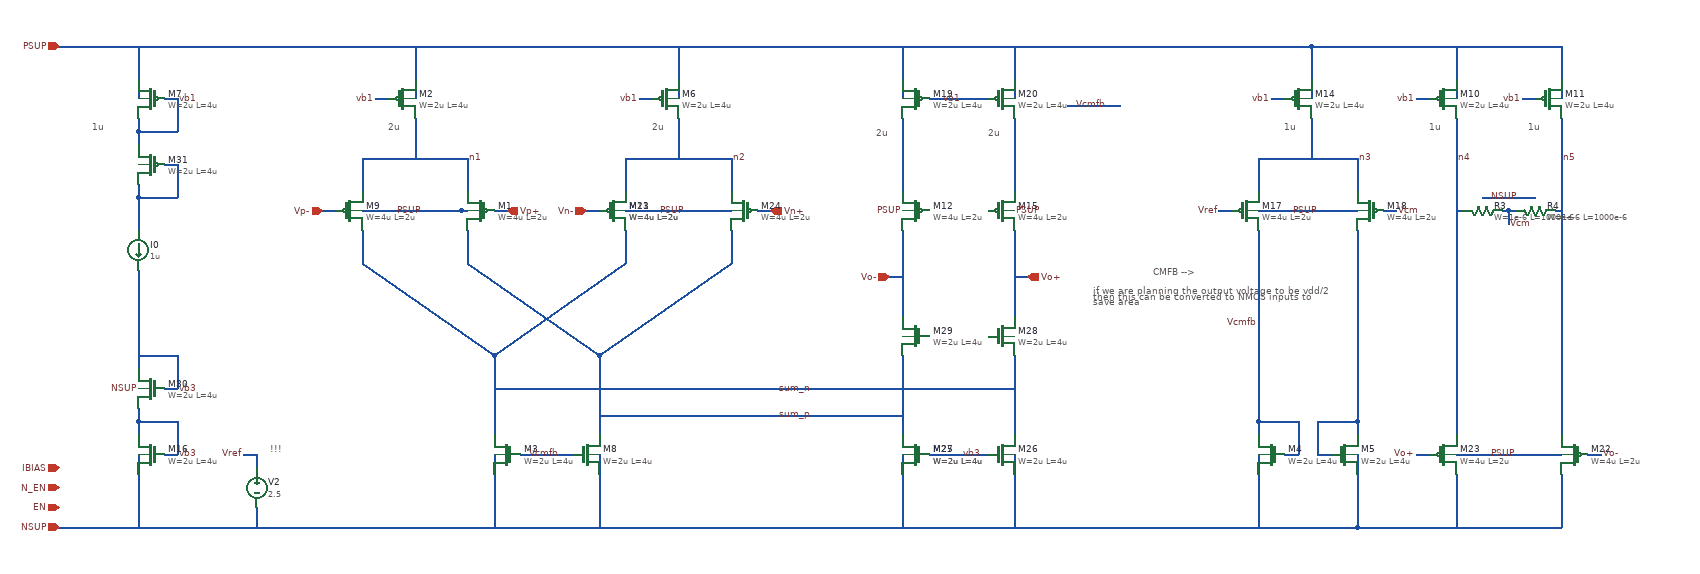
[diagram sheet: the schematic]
v {xschem version=3.4.7 file_version=1.2}
G {}
K {}
V {}
S {}
E {}
T {1u} -620 -620 0 0 0.4 0.4 {}
T {!!!} -350 -130 0 0 0.4 0.4 {}
T {1u} 1410 -620 0 0 0.4 0.4 {}
T {1u} 1560 -620 0 0 0.4 0.4 {}
T {2u} -170 -620 0 0 0.4 0.4 {}
T {2u} 230 -620 0 0 0.4 0.4 {}
T {1u} 1190 -620 0 0 0.4 0.4 {}
T {CMFB -->} 990 -400 0 0 0.4 0.4 {}
T {if we are planning the output voltage to be vdd/2
then this can be converted to NMOS inputs to 
save area} 900 -370 0 0 0.2 0.2 {}
T {2u} 570 -610 0 0 0.4 0.4 {}
T {2u} 740 -610 0 0 0.4 0.4 {}
N -660 -730 -260 -730 {lab=PSUP}
N -670 -730 -660 -730 {lab=PSUP}
N -550 -680 -550 -650 {lab=PSUP}
N -550 -730 -550 -680 {lab=PSUP}
N -550 -600 -490 -600 {lab=vb1}
N -490 -160 -490 -110 {lab=vb3}
N -550 -160 -490 -160 {lab=vb3}
N -550 -160 -550 -140 {lab=vb3}
N -510 -110 -490 -110 {lab=vb3}
N -670 0 -230 0 {lab=NSUP}
N -550 -80 -550 0 {lab=NSUP}
N -370 -30 -370 0 {lab=NSUP}
N -390 -110 -370 -110 {lab=Vref}
N -370 -110 -370 -90 {lab=Vref}
N -550 -110 -550 -80 {lab=NSUP}
N 1390 -110 1410 -110 {lab=Vo+}
N 1390 -110 1410 -110 {lab=Vo+}
N 1650 -110 1670 -110 {lab=Vo-}
N 1390 -650 1410 -650 {lab=vb1}
N 1390 -650 1410 -650 {lab=vb1}
N 1450 -620 1450 -140 {lab=n4}
N 1450 -80 1450 0 {lab=NSUP}
N 1450 -730 1450 -680 {lab=PSUP}
N 1610 -620 1610 -140 {lab=n5}
N 1610 -80 1610 0 {lab=NSUP}
N 1610 -730 1610 -680 {lab=PSUP}
N 1460 -110 1600 -110 {lab=PSUP}
N -210 -560 -210 -510 {lab=n1}
N -50 -560 -50 -510 {lab=n1}
N -10 -80 -10 0 {lab=NSUP}
N -230 0 -40 0 {lab=NSUP}
N -10 -110 -10 -80 {lab=NSUP}
N -10 -150 -10 -140 {lab=sum_n}
N -10 -160 -10 -150 {lab=sum_n}
N -130 -620 -130 -560 {lab=n1}
N -130 -730 -130 -680 {lab=PSUP}
N -210 -450 -210 -400 {lab=sum_n}
N -40 0 340 0 {lab=NSUP}
N 270 -680 270 -650 {lab=PSUP}
N -190 -650 -170 -650 {lab=vb1}
N 210 -650 230 -650 {lab=vb1}
N -10 -480 10 -480 {lab=Vp+}
N -270 -480 -250 -480 {lab=Vp-}
N 1150 -560 1150 -510 {lab=n3}
N 1300 -560 1300 -510 {lab=n3}
N 1230 -620 1230 -560 {lab=n3}
N 1150 -450 1150 -350 {lab=Vcmfb}
N 1300 -450 1300 -400 {lab=#net1}
N 1170 -650 1190 -650 {lab=vb1}
N 1090 -480 1110 -480 {lab=Vref}
N 1150 -80 1150 0 {lab=NSUP}
N 1150 -110 1150 -80 {lab=NSUP}
N 1150 -160 1150 -140 {lab=Vcmfb}
N 1150 -350 1150 -160 {lab=Vcmfb}
N 150 -160 150 -140 {lab=sum_p}
N 1300 -80 1300 0 {lab=NSUP}
N 1300 -350 1300 -160 {lab=#net1}
N 1300 -400 1300 -350 {lab=#net1}
N 1340 -480 1360 -480 {lab=Vcm}
N 150 -110 150 -10 {lab=NSUP}
N 150 -10 150 0 {lab=NSUP}
N 270 -730 270 -680 {lab=PSUP}
N 1230 -620 1230 -560 {lab=n3}
N 1230 -680 1230 -650 {lab=PSUP}
N 1170 -650 1190 -650 {lab=vb1}
N 1230 -730 1230 -680 {lab=PSUP}
N -130 -680 -130 -650 {lab=PSUP}
N -10 -260 -10 -160 {lab=sum_n}
N -210 -480 -60 -480 {lab=PSUP}
N -210 -560 -60 -560 {lab=n1}
N 190 -560 190 -510 {lab=n2}
N 350 -560 350 -510 {lab=n2}
N 190 -560 350 -560 {lab=n2}
N 270 -620 270 -560 {lab=n2}
N -50 -450 -50 -400 {lab=sum_p}
N 350 -450 350 -400 {lab=sum_p}
N 1150 -480 1300 -480 {lab=PSUP}
N 1150 -560 1300 -560 {lab=n3}
N 330 -730 1230 -730 {lab=PSUP}
N 730 0 1300 0 {lab=NSUP}
N 1300 -110 1300 -80 {lab=NSUP}
N 1190 -110 1210 -110 {lab=Vcmfb}
N 1210 -160 1210 -110 {lab=Vcmfb}
N 1150 -160 1210 -160 {lab=Vcmfb}
N 1240 -110 1260 -110 {lab=#net1}
N 1240 -120 1240 -110 {lab=#net1}
N 1240 -160 1240 -120 {lab=#net1}
N 1240 -160 1300 -160 {lab=#net1}
N 1300 -160 1300 -140 {lab=#net1}
N 40 -110 110 -110 {lab=Vcmfb}
N 130 -480 150 -480 {lab=Vn-}
N 390 -480 410 -480 {lab=Vn+}
N 30 -110 40 -110 {lab=Vcmfb}
N -260 -730 -60 -730 {lab=PSUP}
N -60 -560 -50 -560 {lab=n1}
N -60 -480 -50 -480 {lab=PSUP}
N -210 -400 -10 -260 {lab=sum_n}
N -10 -260 190 -400 {lab=sum_n}
N -210 -480 -60 -480 {lab=PSUP}
N 190 -480 340 -480 {lab=PSUP}
N 190 -450 190 -400 {lab=sum_n}
N -50 -400 150 -260 {lab=sum_p}
N 150 -260 350 -400 {lab=sum_p}
N 150 -260 150 -160 {lab=sum_p}
N 340 -480 350 -480 {lab=PSUP}
N -510 -650 -490 -650 {lab=vb1}
N 1530 -480 1540 -480 {lab=Vcm}
N 1520 -480 1530 -480 {lab=Vcm}
N 1530 -480 1530 -460 {lab=Vcm}
N 1490 -500 1530 -500 {lab=NSUP}
N 1530 -500 1570 -500 {lab=NSUP}
N 1450 -110 1460 -110 {lab=PSUP}
N 1600 -110 1610 -110 {lab=PSUP}
N 1450 -480 1460 -480 {lab=n4}
N 1600 -480 1610 -480 {lab=n5}
N 1300 0 1610 0 {lab=NSUP}
N 1230 -730 1610 -730 {lab=PSUP}
N 1450 -680 1450 -650 {lab=PSUP}
N 1610 -680 1610 -650 {lab=PSUP}
N 1550 -650 1570 -650 {lab=vb1}
N 1550 -650 1570 -650 {lab=vb1}
N -60 -730 330 -730 {lab=PSUP}
N 340 0 730 0 {lab=NSUP}
N 870 -640 940 -640 {lab=Vcmfb}
N 860 -640 870 -640 {lab=Vcmfb}
N 610 -110 610 0 {lab=NSUP}
N 780 -110 780 0 {lab=NSUP}
N 650 -110 740 -110 {lab=vb3}
N 610 -450 610 -320 {lab=Vo-}
N 610 -620 610 -510 {lab=#net2}
N 610 -730 610 -650 {lab=PSUP}
N 650 -650 740 -650 {lab=vb1}
N 780 -730 780 -650 {lab=PSUP}
N 780 -620 780 -510 {lab=#net3}
N 780 -380 800 -380 {lab=Vo+}
N 780 -450 780 -320 {lab=Vo+}
N 590 -380 610 -380 {lab=Vo-}
N 610 -260 610 -140 {lab=sum_p}
N 780 -260 780 -140 {lab=sum_n}
N 150 -170 610 -170 {lab=sum_p}
N -10 -210 780 -210 {lab=sum_n}
N -490 -260 -490 -210 {lab=vb3}
N -550 -260 -490 -260 {lab=vb3}
N -550 -260 -550 -240 {lab=vb3}
N -510 -210 -490 -210 {lab=vb3}
N -550 -180 -550 -160 {lab=vb3}
N -550 -390 -550 -240 {lab=vb3}
N -490 -650 -490 -600 {lab=vb1}
N -550 -620 -550 -600 {lab=vb1}
N -550 -500 -490 -500 {lab=#net4}
N -490 -550 -490 -500 {lab=#net4}
N -550 -520 -550 -500 {lab=#net4}
N -510 -550 -490 -550 {lab=#net4}
N -550 -600 -550 -580 {lab=vb1}
N -550 -500 -550 -450 {lab=#net4}
C {noconn.sym} -670 -60 0 1 {name=l1}
C {noconn.sym} -670 -30 0 1 {name=l2}
C {ipin.sym} -670 -730 0 0 {name=p19 lab=PSUP
}
C {ipin.sym} -670 0 0 0 {name=p20 lab=NSUP
}
C {ipin.sym} -670 -60 0 0 {name=p21 lab=N_EN

}
C {ipin.sym} -670 -30 0 0 {name=p22 lab=EN
}
C {ipin.sym} -670 -90 0 0 {name=p9 lab=IBIAS


}
C {isource.sym} -550 -420 0 0 {name=I0 value=1u}
C {symbols/pfet_06v0.sym} -530 -650 0 1 {name=M7
L=4u
W=2u
nf=1
m=4
ad="'int((nf+1)/2) * W/nf * 0.18u'"
pd="'2*int((nf+1)/2) * (W/nf + 0.18u)'"
as="'int((nf+2)/2) * W/nf * 0.18u'"
ps="'2*int((nf+2)/2) * (W/nf + 0.18u)'"
nrd="'0.18u / W'" nrs="'0.18u / W'"
sa=0 sb=0 sd=0
model=pfet_06v0
spiceprefix=X
}
C {lab_pin.sym} -490 -650 0 1 {name=p8 sig_type=std_logic lab=vb1}
C {noconn.sym} -670 -90 0 1 {name=l3}
C {symbols/nfet_06v0_nvt.sym} -530 -110 0 1 {name=M16
L=4u
W=2u
nf=1
m=4
ad="'int((nf+1)/2) * W/nf * 0.18u'"
pd="'2*int((nf+1)/2) * (W/nf + 0.18u)'"
as="'int((nf+2)/2) * W/nf * 0.18u'"
ps="'2*int((nf+2)/2) * (W/nf + 0.18u)'"
nrd="'0.18u / W'" nrs="'0.18u / W'"
sa=0 sb=0 sd=0
model=nfet_06v0
spiceprefix=X
}
C {lab_pin.sym} -490 -110 2 0 {name=p29 sig_type=std_logic lab=vb3}
C {vsource.sym} -370 -60 0 0 {name=V2 value=2.5 savecurrent=false}
C {lab_pin.sym} -390 -110 0 0 {name=p30 sig_type=std_logic lab=Vref}
C {lab_pin.sym} 1390 -110 0 0 {name=p35 sig_type=std_logic lab=Vo+}
C {lab_pin.sym} 1670 -110 0 1 {name=p36 sig_type=std_logic lab=Vo-}
C {symbols/pfet_06v0.sym} 1630 -110 0 1 {name=M22
L=2u
W=4u
nf=5
m=4
ad="'int((nf+1)/2) * W/nf * 0.18u'"
pd="'2*int((nf+1)/2) * (W/nf + 0.18u)'"
as="'int((nf+2)/2) * W/nf * 0.18u'"
ps="'2*int((nf+2)/2) * (W/nf + 0.18u)'"
nrd="'0.18u / W'" nrs="'0.18u / W'"
sa=0 sb=0 sd=0
model=pfet_06v0
spiceprefix=X
}
C {symbols/pfet_06v0.sym} 1430 -110 0 0 {name=M23
L=2u
W=4u
nf=5
m=4
ad="'int((nf+1)/2) * W/nf * 0.18u'"
pd="'2*int((nf+1)/2) * (W/nf + 0.18u)'"
as="'int((nf+2)/2) * W/nf * 0.18u'"
ps="'2*int((nf+2)/2) * (W/nf + 0.18u)'"
nrd="'0.18u / W'" nrs="'0.18u / W'"
sa=0 sb=0 sd=0
model=pfet_06v0
spiceprefix=X
}
C {symbols/pfet_06v0.sym} -230 -480 0 0 {name=M9
L=2u
W=4u
nf=5
m=10
ad="'int((nf+1)/2) * W/nf * 0.18u'"
pd="'2*int((nf+1)/2) * (W/nf + 0.18u)'"
as="'int((nf+2)/2) * W/nf * 0.18u'"
ps="'2*int((nf+2)/2) * (W/nf + 0.18u)'"
nrd="'0.18u / W'" nrs="'0.18u / W'"
sa=0 sb=0 sd=0
model=pfet_06v0
spiceprefix=X
}
C {symbols/pfet_06v0.sym} -30 -480 0 1 {name=M1
L=2u
W=4u
nf=5
m=10
ad="'int((nf+1)/2) * W/nf * 0.18u'"
pd="'2*int((nf+1)/2) * (W/nf + 0.18u)'"
as="'int((nf+2)/2) * W/nf * 0.18u'"
ps="'2*int((nf+2)/2) * (W/nf + 0.18u)'"
nrd="'0.18u / W'" nrs="'0.18u / W'"
sa=0 sb=0 sd=0
model=pfet_06v0
spiceprefix=X
}
C {lab_pin.sym} -160 -480 2 0 {name=p6 sig_type=std_logic lab=PSUP}
C {symbols/pfet_06v0.sym} -150 -650 0 0 {name=M2
L=4u
W=2u
nf=1
m=8
ad="'int((nf+1)/2) * W/nf * 0.18u'"
pd="'2*int((nf+1)/2) * (W/nf + 0.18u)'"
as="'int((nf+2)/2) * W/nf * 0.18u'"
ps="'2*int((nf+2)/2) * (W/nf + 0.18u)'"
nrd="'0.18u / W'" nrs="'0.18u / W'"
sa=0 sb=0 sd=0
model=pfet_06v0
spiceprefix=X
}
C {symbols/nfet_06v0_nvt.sym} 10 -110 0 1 {name=M3
L=4u
W=2u
nf=1
m=16
ad="'int((nf+1)/2) * W/nf * 0.18u'"
pd="'2*int((nf+1)/2) * (W/nf + 0.18u)'"
as="'int((nf+2)/2) * W/nf * 0.18u'"
ps="'2*int((nf+2)/2) * (W/nf + 0.18u)'"
nrd="'0.18u / W'" nrs="'0.18u / W'"
sa=0 sb=0 sd=0
model=nfet_06v0
spiceprefix=X
}
C {symbols/pfet_06v0.sym} 250 -650 0 0 {name=M6
L=4u
W=2u
nf=1
m=8
ad="'int((nf+1)/2) * W/nf * 0.18u'"
pd="'2*int((nf+1)/2) * (W/nf + 0.18u)'"
as="'int((nf+2)/2) * W/nf * 0.18u'"
ps="'2*int((nf+2)/2) * (W/nf + 0.18u)'"
nrd="'0.18u / W'" nrs="'0.18u / W'"
sa=0 sb=0 sd=0
model=pfet_06v0
spiceprefix=X
}
C {symbols/nfet_06v0_nvt.sym} 130 -110 0 0 {name=M8
L=4u
W=2u
nf=1
m=16
ad="'int((nf+1)/2) * W/nf * 0.18u'"
pd="'2*int((nf+1)/2) * (W/nf + 0.18u)'"
as="'int((nf+2)/2) * W/nf * 0.18u'"
ps="'2*int((nf+2)/2) * (W/nf + 0.18u)'"
nrd="'0.18u / W'" nrs="'0.18u / W'"
sa=0 sb=0 sd=0
model=nfet_06v0
spiceprefix=X
}
C {lab_pin.sym} -190 -650 0 0 {name=p16 sig_type=std_logic lab=vb1}
C {lab_pin.sym} 210 -650 0 0 {name=p17 sig_type=std_logic lab=vb1}
C {ipin.sym} 10 -480 0 1 {name=p23 lab=Vp+

}
C {ipin.sym} -270 -480 0 0 {name=p24 lab=Vp-

}
C {ipin.sym} 410 -480 0 1 {name=p25 lab=Vn+

}
C {ipin.sym} 130 -480 0 0 {name=p26 lab=Vn-

}
C {symbols/nfet_06v0_nvt.sym} 1170 -110 0 1 {name=M4
L=4u
W=2u
nf=1
m=4
ad="'int((nf+1)/2) * W/nf * 0.18u'"
pd="'2*int((nf+1)/2) * (W/nf + 0.18u)'"
as="'int((nf+2)/2) * W/nf * 0.18u'"
ps="'2*int((nf+2)/2) * (W/nf + 0.18u)'"
nrd="'0.18u / W'" nrs="'0.18u / W'"
sa=0 sb=0 sd=0
model=nfet_06v0
spiceprefix=X
}
C {symbols/nfet_06v0_nvt.sym} 1280 -110 0 0 {name=M5
L=4u
W=2u
nf=1
m=4
ad="'int((nf+1)/2) * W/nf * 0.18u'"
pd="'2*int((nf+1)/2) * (W/nf + 0.18u)'"
as="'int((nf+2)/2) * W/nf * 0.18u'"
ps="'2*int((nf+2)/2) * (W/nf + 0.18u)'"
nrd="'0.18u / W'" nrs="'0.18u / W'"
sa=0 sb=0 sd=0
model=nfet_06v0
spiceprefix=X
}
C {lab_pin.sym} 1170 -650 0 0 {name=p1 sig_type=std_logic lab=vb1}
C {symbols/pfet_06v0.sym} 1210 -650 0 0 {name=M14
L=4u
W=2u
nf=1
m=4
ad="'int((nf+1)/2) * W/nf * 0.18u'"
pd="'2*int((nf+1)/2) * (W/nf + 0.18u)'"
as="'int((nf+2)/2) * W/nf * 0.18u'"
ps="'2*int((nf+2)/2) * (W/nf + 0.18u)'"
nrd="'0.18u / W'" nrs="'0.18u / W'"
sa=0 sb=0 sd=0
model=pfet_06v0
spiceprefix=X
}
C {lab_pin.sym} 1090 -480 0 0 {name=p7 sig_type=std_logic lab=Vref}
C {symbols/pfet_06v0.sym} 1130 -480 0 0 {name=M17
L=2u
W=4u
nf=5
m=4
ad="'int((nf+1)/2) * W/nf * 0.18u'"
pd="'2*int((nf+1)/2) * (W/nf + 0.18u)'"
as="'int((nf+2)/2) * W/nf * 0.18u'"
ps="'2*int((nf+2)/2) * (W/nf + 0.18u)'"
nrd="'0.18u / W'" nrs="'0.18u / W'"
sa=0 sb=0 sd=0
model=pfet_06v0
spiceprefix=X
}
C {symbols/pfet_06v0.sym} 1320 -480 0 1 {name=M18
L=2u
W=4u
nf=5
m=4
ad="'int((nf+1)/2) * W/nf * 0.18u'"
pd="'2*int((nf+1)/2) * (W/nf + 0.18u)'"
as="'int((nf+2)/2) * W/nf * 0.18u'"
ps="'2*int((nf+2)/2) * (W/nf + 0.18u)'"
nrd="'0.18u / W'" nrs="'0.18u / W'"
sa=0 sb=0 sd=0
model=pfet_06v0
spiceprefix=X
}
C {lab_pin.sym} -50 -560 2 0 {name=p11 sig_type=std_logic lab=n1}
C {lab_pin.sym} 350 -560 2 0 {name=p14 sig_type=std_logic lab=n2}
C {lab_pin.sym} 1300 -560 2 0 {name=p15 sig_type=std_logic lab=n3}
C {lab_pin.sym} 1150 -310 0 0 {name=p12 sig_type=std_logic lab=Vcmfb}
C {lab_pin.sym} 90 -110 0 0 {name=p18 sig_type=std_logic lab=Vcmfb}
C {symbols/pfet_06v0.sym} 170 -480 0 0 {name=M21
L=2u
W=4u
nf=5
m=10
ad="'int((nf+1)/2) * W/nf * 0.18u'"
pd="'2*int((nf+1)/2) * (W/nf + 0.18u)'"
as="'int((nf+2)/2) * W/nf * 0.18u'"
ps="'2*int((nf+2)/2) * (W/nf + 0.18u)'"
nrd="'0.18u / W'" nrs="'0.18u / W'"
sa=0 sb=0 sd=0
model=pfet_06v0
spiceprefix=X
}
C {symbols/pfet_06v0.sym} 370 -480 0 1 {name=M24
L=2u
W=4u
nf=5
m=10
ad="'int((nf+1)/2) * W/nf * 0.18u'"
pd="'2*int((nf+1)/2) * (W/nf + 0.18u)'"
as="'int((nf+2)/2) * W/nf * 0.18u'"
ps="'2*int((nf+2)/2) * (W/nf + 0.18u)'"
nrd="'0.18u / W'" nrs="'0.18u / W'"
sa=0 sb=0 sd=0
model=pfet_06v0
spiceprefix=X
}
C {lab_pin.sym} 240 -480 2 0 {name=p28 sig_type=std_logic lab=PSUP}
C {lab_pin.sym} 1360 -480 0 1 {name=p32 sig_type=std_logic lab=Vcm}
C {lab_pin.sym} 1200 -480 2 0 {name=p42 sig_type=std_logic lab=PSUP}
C {symbols/ppolyf_u_3k.sym} 1490 -480 1 0 {name=R3
W=1e-6
L=1000e-6
model=ppolyf_u_3k
spiceprefix=X
m=1}
C {symbols/ppolyf_u_3k.sym} 1570 -480 1 0 {name=R4
W=1e-6
L=1000e-6
model=ppolyf_u_3k
spiceprefix=X
m=1}
C {lab_pin.sym} 1530 -460 0 1 {name=p3 sig_type=std_logic lab=Vcm}
C {lab_pin.sym} 1500 -500 0 1 {name=p13 sig_type=std_logic lab=NSUP}
C {lab_pin.sym} 1450 -560 2 0 {name=p4 sig_type=std_logic lab=n4}
C {lab_pin.sym} 1610 -560 2 0 {name=p5 sig_type=std_logic lab=n5}
C {lab_pin.sym} 1500 -110 2 0 {name=p33 sig_type=std_logic lab=PSUP}
C {symbols/pfet_06v0.sym} 1430 -650 0 0 {name=M10
L=4u
W=2u
nf=1
m=4
ad="'int((nf+1)/2) * W/nf * 0.18u'"
pd="'2*int((nf+1)/2) * (W/nf + 0.18u)'"
as="'int((nf+2)/2) * W/nf * 0.18u'"
ps="'2*int((nf+2)/2) * (W/nf + 0.18u)'"
nrd="'0.18u / W'" nrs="'0.18u / W'"
sa=0 sb=0 sd=0
model=pfet_06v0
spiceprefix=X
}
C {symbols/pfet_06v0.sym} 1590 -650 0 0 {name=M11
L=4u
W=2u
nf=1
m=4
ad="'int((nf+1)/2) * W/nf * 0.18u'"
pd="'2*int((nf+1)/2) * (W/nf + 0.18u)'"
as="'int((nf+2)/2) * W/nf * 0.18u'"
ps="'2*int((nf+2)/2) * (W/nf + 0.18u)'"
nrd="'0.18u / W'" nrs="'0.18u / W'"
sa=0 sb=0 sd=0
model=pfet_06v0
spiceprefix=X
}
C {lab_pin.sym} 1390 -650 0 0 {name=p10 sig_type=std_logic lab=vb1}
C {lab_pin.sym} 1550 -650 0 0 {name=p31 sig_type=std_logic lab=vb1}
C {symbols/pfet_06v0.sym} 170 -480 0 0 {name=M13
L=2u
W=4u
nf=5
m=10
ad="'int((nf+1)/2) * W/nf * 0.18u'"
pd="'2*int((nf+1)/2) * (W/nf + 0.18u)'"
as="'int((nf+2)/2) * W/nf * 0.18u'"
ps="'2*int((nf+2)/2) * (W/nf + 0.18u)'"
nrd="'0.18u / W'" nrs="'0.18u / W'"
sa=0 sb=0 sd=0
model=pfet_06v0
spiceprefix=X
}
C {symbols/pfet_06v0.sym} 630 -480 0 1 {name=M12
L=2u
W=4u
nf=5
m=10
ad="'int((nf+1)/2) * W/nf * 0.18u'"
pd="'2*int((nf+1)/2) * (W/nf + 0.18u)'"
as="'int((nf+2)/2) * W/nf * 0.18u'"
ps="'2*int((nf+2)/2) * (W/nf + 0.18u)'"
nrd="'0.18u / W'" nrs="'0.18u / W'"
sa=0 sb=0 sd=0
model=pfet_06v0
spiceprefix=X
}
C {symbols/pfet_06v0.sym} 760 -480 0 0 {name=M15
L=2u
W=4u
nf=5
m=10
ad="'int((nf+1)/2) * W/nf * 0.18u'"
pd="'2*int((nf+1)/2) * (W/nf + 0.18u)'"
as="'int((nf+2)/2) * W/nf * 0.18u'"
ps="'2*int((nf+2)/2) * (W/nf + 0.18u)'"
nrd="'0.18u / W'" nrs="'0.18u / W'"
sa=0 sb=0 sd=0
model=pfet_06v0
spiceprefix=X
}
C {lab_pin.sym} 610 -480 2 1 {name=p34 sig_type=std_logic lab=PSUP}
C {symbols/pfet_06v0.sym} 630 -650 0 1 {name=M19
L=4u
W=2u
nf=1
m=8
ad="'int((nf+1)/2) * W/nf * 0.18u'"
pd="'2*int((nf+1)/2) * (W/nf + 0.18u)'"
as="'int((nf+2)/2) * W/nf * 0.18u'"
ps="'2*int((nf+2)/2) * (W/nf + 0.18u)'"
nrd="'0.18u / W'" nrs="'0.18u / W'"
sa=0 sb=0 sd=0
model=pfet_06v0
spiceprefix=X
}
C {symbols/pfet_06v0.sym} 760 -650 0 0 {name=M20
L=4u
W=2u
nf=1
m=8
ad="'int((nf+1)/2) * W/nf * 0.18u'"
pd="'2*int((nf+1)/2) * (W/nf + 0.18u)'"
as="'int((nf+2)/2) * W/nf * 0.18u'"
ps="'2*int((nf+2)/2) * (W/nf + 0.18u)'"
nrd="'0.18u / W'" nrs="'0.18u / W'"
sa=0 sb=0 sd=0
model=pfet_06v0
spiceprefix=X
}
C {opin.sym} 590 -380 0 1 {name=p27 lab=Vo-}
C {opin.sym} 800 -380 0 0 {name=p2 lab=Vo+}
C {lab_pin.sym} 780 -480 2 0 {name=p37 sig_type=std_logic lab=PSUP}
C {symbols/nfet_06v0_nvt.sym} 630 -110 0 1 {name=M25
L=4u
W=2u
nf=1
m=16
ad="'int((nf+1)/2) * W/nf * 0.18u'"
pd="'2*int((nf+1)/2) * (W/nf + 0.18u)'"
as="'int((nf+2)/2) * W/nf * 0.18u'"
ps="'2*int((nf+2)/2) * (W/nf + 0.18u)'"
nrd="'0.18u / W'" nrs="'0.18u / W'"
sa=0 sb=0 sd=0
model=nfet_06v0
spiceprefix=X
}
C {symbols/nfet_06v0_nvt.sym} 760 -110 0 0 {name=M26
L=4u
W=2u
nf=1
m=16
ad="'int((nf+1)/2) * W/nf * 0.18u'"
pd="'2*int((nf+1)/2) * (W/nf + 0.18u)'"
as="'int((nf+2)/2) * W/nf * 0.18u'"
ps="'2*int((nf+2)/2) * (W/nf + 0.18u)'"
nrd="'0.18u / W'" nrs="'0.18u / W'"
sa=0 sb=0 sd=0
model=nfet_06v0
spiceprefix=X
}
C {lab_pin.sym} 920 -640 0 0 {name=p39 sig_type=std_logic lab=Vcmfb}
C {lab_pin.sym} 700 -110 2 0 {name=p38 sig_type=std_logic lab=vb3}
C {symbols/nfet_06v0_nvt.sym} 630 -110 0 1 {name=M27
L=4u
W=2u
nf=1
m=16
ad="'int((nf+1)/2) * W/nf * 0.18u'"
pd="'2*int((nf+1)/2) * (W/nf + 0.18u)'"
as="'int((nf+2)/2) * W/nf * 0.18u'"
ps="'2*int((nf+2)/2) * (W/nf + 0.18u)'"
nrd="'0.18u / W'" nrs="'0.18u / W'"
sa=0 sb=0 sd=0
model=nfet_06v0
spiceprefix=X
}
C {symbols/nfet_06v0_nvt.sym} 760 -290 0 0 {name=M28
L=4u
W=2u
nf=1
m=16
ad="'int((nf+1)/2) * W/nf * 0.18u'"
pd="'2*int((nf+1)/2) * (W/nf + 0.18u)'"
as="'int((nf+2)/2) * W/nf * 0.18u'"
ps="'2*int((nf+2)/2) * (W/nf + 0.18u)'"
nrd="'0.18u / W'" nrs="'0.18u / W'"
sa=0 sb=0 sd=0
model=nfet_06v0
spiceprefix=X
}
C {symbols/nfet_06v0_nvt.sym} 630 -290 0 1 {name=M29
L=4u
W=2u
nf=1
m=16
ad="'int((nf+1)/2) * W/nf * 0.18u'"
pd="'2*int((nf+1)/2) * (W/nf + 0.18u)'"
as="'int((nf+2)/2) * W/nf * 0.18u'"
ps="'2*int((nf+2)/2) * (W/nf + 0.18u)'"
nrd="'0.18u / W'" nrs="'0.18u / W'"
sa=0 sb=0 sd=0
model=nfet_06v0
spiceprefix=X
}
C {lab_pin.sym} 700 -650 0 0 {name=p40 sig_type=std_logic lab=vb1}
C {lab_pin.sym} 420 -170 2 0 {name=p41 sig_type=std_logic lab=sum_p}
C {lab_pin.sym} 420 -210 2 0 {name=p43 sig_type=std_logic lab=sum_n}
C {symbols/nfet_06v0_nvt.sym} -530 -210 0 1 {name=M30
L=4u
W=2u
nf=1
m=4
ad="'int((nf+1)/2) * W/nf * 0.18u'"
pd="'2*int((nf+1)/2) * (W/nf + 0.18u)'"
as="'int((nf+2)/2) * W/nf * 0.18u'"
ps="'2*int((nf+2)/2) * (W/nf + 0.18u)'"
nrd="'0.18u / W'" nrs="'0.18u / W'"
sa=0 sb=0 sd=0
model=nfet_06v0
spiceprefix=X
}
C {lab_pin.sym} -490 -210 2 0 {name=p44 sig_type=std_logic lab=vb3}
C {lab_pin.sym} -550 -210 2 1 {name=p45 sig_type=std_logic lab=NSUP}
C {symbols/pfet_06v0.sym} -530 -550 0 1 {name=M31
L=4u
W=2u
nf=1
m=4
ad="'int((nf+1)/2) * W/nf * 0.18u'"
pd="'2*int((nf+1)/2) * (W/nf + 0.18u)'"
as="'int((nf+2)/2) * W/nf * 0.18u'"
ps="'2*int((nf+2)/2) * (W/nf + 0.18u)'"
nrd="'0.18u / W'" nrs="'0.18u / W'"
sa=0 sb=0 sd=0
model=pfet_06v0
spiceprefix=X
}
